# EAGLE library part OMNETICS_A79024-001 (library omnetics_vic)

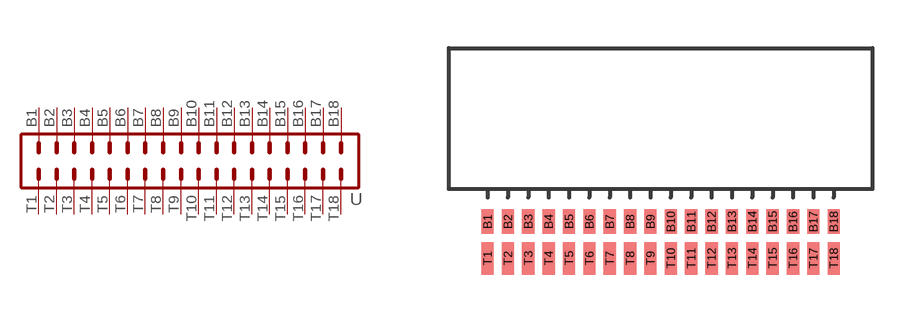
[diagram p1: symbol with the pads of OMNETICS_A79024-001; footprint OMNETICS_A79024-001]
Designator prefix -

## OMNETICS_A79024-001  [OMNETICS_A79024-001]
B1  B1  pas
B2  B2  pas
B3  B3  pas
B4  B4  pas
B5  B5  pas
B6  B6  pas
B7  B7  pas
B8  B8  pas
B9  B9  pas
B10  B10  pas
B11  B11  pas
B12  B12  pas
B13  B13  pas
B14  B14  pas
B15  B15  pas
B16  B16  pas
B17  B17  pas
B18  B18  pas
T1  T1  pas
T2  T2  pas
T3  T3  pas
T4  T4  pas
T5  T5  pas
T6  T6  pas
T7  T7  pas
T8  T8  pas
T9  T9  pas
T10  T10  pas
T11  T11  pas
T12  T12  pas
T13  T13  pas
T14  T14  pas
T15  T15  pas
T16  T16  pas
T17  T17  pas
T18  T18  pas

## Footprint OMNETICS_A79024-001 (pad centres in mm)
smd 0.381 x 0.762: B1 -5.397,-0.933; B2 -4.763,-0.933; B3 -4.128,-0.933; B4 -3.493,-0.933; B5 -2.857,-0.933; B6 -2.223,-0.933; B7 -1.587,-0.933; B8 -0.953,-0.933; B9 -0.318,-0.933; B10 0.318,-0.933; B11 0.953,-0.933; B12 1.587,-0.933; B13 2.223,-0.933; B14 2.857,-0.933; B15 3.493,-0.933; B16 4.128,-0.933; B17 4.763,-0.933; B18 5.397,-0.933
smd 0.381 x 1.016: T1 -5.397,-2.076; T2 -4.763,-2.076; T3 -4.128,-2.076; T4 -3.493,-2.076; T5 -2.857,-2.076; T6 -2.223,-2.076; T7 -1.587,-2.076; T8 -0.953,-2.076; T9 -0.318,-2.076; T10 0.318,-2.076; T11 0.953,-2.076; T12 1.587,-2.076; T13 2.223,-2.076; T14 2.857,-2.076; T15 3.493,-2.076; T16 4.128,-2.076; T17 4.763,-2.076; T18 5.397,-2.076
